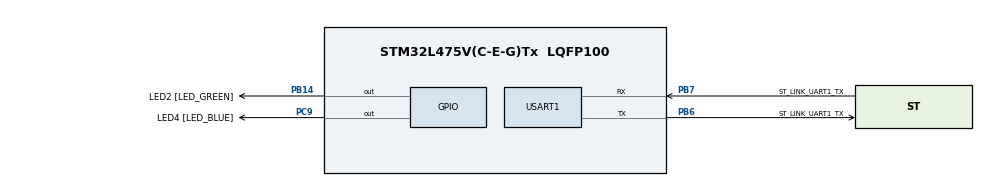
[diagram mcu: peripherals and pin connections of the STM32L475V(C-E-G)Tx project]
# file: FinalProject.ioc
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Mcu.Family=STM32L4
Mcu.Name=STM32L475V(C-E-G)Tx
Mcu.Package=LQFP100
NVIC.PriorityGroup=NVIC_PRIORITYGROUP_4
NVIC.RTC_Alarm_IRQn=true\:0\:0\:false\:false\:true\:true\:true\:true
NVIC.TIM2_IRQn=true\:0\:0\:false\:false\:true\:true\:true\:true
NVIC.TIM3_IRQn=true\:0\:0\:false\:false\:true\:true\:true\:true
NVIC.USART1_IRQn=true\:0\:0\:false\:false\:true\:true\:true\:true
PB14.GPIO_Label=LED2 [LED_GREEN]
PB14.Signal=GPIO_Output
PB6.GPIO_Label=ST_LINK_UART1_TX
PB6.Mode=Asynchronous
PB6.Signal=USART1_TX
PB7.GPIO_Label=ST_LINK_UART1_TX
PB7.Mode=Asynchronous
PB7.Signal=USART1_RX
PC9.GPIO_Label=LED4 [LED_BLUE]
PC9.Signal=GPIO_Output
ProjectManager.HeapSize=0x200
ProjectManager.StackSize=0x400
ProjectManager.TargetToolchain=STM32CubeIDE
RCC.HSE_VALUE=8000000
RCC.HSI_VALUE=16000000
RCC.LSE_VALUE=32768
RCC.MSI_VALUE=4000000
RCC.VCOOutputFreq_Value=32000000
RTC.Alarm-Alarm\ A=RTC_ALARM_A
USART1.VirtualMode-Asynchronous=VM_ASYNC
VP_IWDG_VS_IWDG.Mode=IWDG_Activate
VP_RTC_VS_RTC_Activate.Mode=RTC_Enabled
VP_RTC_VS_RTC_Alarm_A_Intern.Mode=Alarm A
VP_RTC_VS_RTC_Calendar.Mode=RTC_Calendar
VP_TIM2_VS_ClockSourceINT.Mode=Internal
VP_TIM3_VS_ClockSourceINT.Mode=Internal
board=custom

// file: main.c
/* USER CODE BEGIN Header */
/**
  ******************************************************************************
  * @file           : main.c
  * @brief          : Final Project
  * @author			: Fidel Quezada Guzman
  *
  ******************************************************************************
  * @attention
  *
  * Copyright (c) 2024 STMicroelectronics.
  * All rights reserved.
  *
  * This software is licensed under terms that can be found in the LICENSE file
  * in the root directory of this software component.
  * If no LICENSE file comes with this software, it is provided AS-IS.
  *
  ******************************************************************************
  */
/* USER CODE END Header */
#include "main.h"
/* USER CODE BEGIN Includes */
#include "string.h"
#include <stdio.h>						// Standard C Lib
#include "stm32l4xx.h"  				// STM32f4 series
/* USER CODE END Includes */
/* USER CODE BEGIN PTD */

// Boolean functionality
typedef enum
{
	FALSE, TRUE
} boolean;
/* USER CODE END PTD */
IWDG_HandleTypeDef hiwdg;
RTC_HandleTypeDef hrtc;
TIM_HandleTypeDef htim2;
TIM_HandleTypeDef htim3;
UART_HandleTypeDef huart1;
/* USER CODE BEGIN PV */

// UART input/output variables
char input[1] = { 0 };
volatile boolean TX_completed = FALSE;
char buffer[50];							// for printing w/ variables

// SW interrupt flag
volatile boolean SW_interrupt_detected = FALSE;

// Timer3 variables
volatile uint32_t timer3_count = 0;
const uint32_t MAX_COUNT = 10;
volatile boolean timer3_start = FALSE;

// RTC Alarm variables
volatile boolean rtc_alarm = FALSE;

/* USER CODE END PV */
void SystemClock_Config(void);
static void MX_GPIO_Init(void);
static void MX_IWDG_Init(void);
static void MX_RTC_Init(void);
static void MX_TIM2_Init(void);
static void MX_TIM3_Init(void);
static void MX_USART1_UART_Init(void);
/* USER CODE BEGIN PFP */

// Display the string on Terminal
void logMsg(UART_HandleTypeDef *huart, char _out[])
{
	// Run till completed
	HAL_UART_Transmit_IT(huart, (uint8_t *) _out, strlen(_out));
	do {
	} while (!TX_completed);
	TX_completed = FALSE;		// Reset once TX is completed
}

// Receive character from terminal
char logGetMsg(UART_HandleTypeDef *huart)
{
	HAL_UART_Receive_IT(huart, (uint8_t *) input, 1);
	return input[0];
}

// Board LEDs Toggle
void toggleGreenLED()
{
	HAL_GPIO_TogglePin(GPIOB, LED2_Pin);
	myDelay2(500);  							// Add custom delay made from SysTick
}
void toggleBlueLED()
{
	HAL_GPIO_TogglePin(GPIOC, LED4_Pin);
    myDelay1(500);								// Add custom delay made from Timer2
}

// Enable SW interrupt
void SWInterrupt(uint32_t IRQn)
{
	NVIC->STIR = IRQn;	// Trigger SW interrupt
}

// Custom Delay using Timer2
void myDelay1(uint32_t val)
{
    // Calculate required number of timer ticks based on desired delay
    uint32_t ticks = (HAL_RCC_GetHCLKFreq() / (htim2.Init.Prescaler + 1)) * val / 1000;

    // Configure Timer2 to start in interrupt mode
    HAL_TIM_Base_Start_IT(&htim2);

    // Reset Timer2 counter
    __HAL_TIM_SET_COUNTER(&htim2, 0);

    // Wait for required number of timer ticks. Get_Couter retrieves current value of Timer2
    while (__HAL_TIM_GET_COUNTER(&htim2) < ticks)
    {
        // Wait
    }
    // Stop Timer2
    HAL_TIM_Base_Stop_IT(&htim2);
}

// Custom Delay using SysTick to generate interrupts at specific freq, then wait for specific # of interrupts
void myDelay2(uint32_t val)
{
    // Configure SysTick to generate interrupts every 1ms
    SysTick_Config(SystemCoreClock / 1000);

    // Calculate required # of SysTick ticks based on the desired delay (in ms)
    uint32_t ticks = val;

    // Wait for # of SysTick ticks
    while (ticks > 0)
    {
        if (SysTick->CTRL & SysTick_CTRL_COUNTFLAG_Msk)
        {
            ticks--;
        }
    }

    // Disable SysTick
    SysTick->CTRL &= ~SysTick_CTRL_ENABLE_Msk;
}

/* USER CODE END PFP */
int main(void)
{
	/* MCU Configuration--------------------------------------------------------*/
	/* Reset of all peripherals, Initializes the Flash interface and the Systick. */
	HAL_Init();
	/* Configure the system clock */
	SystemClock_Config();
	/* Initialize all configured peripherals */
	MX_GPIO_Init();
	MX_IWDG_Init();
	MX_RTC_Init();
	MX_TIM2_Init();
	MX_TIM3_Init();
	MX_USART1_UART_Init();
	/* USER CODE BEGIN 2 */
	// Initial User Prompt
	logMsg(&huart1, "\n\n\n");
	logMsg(&huart1, "****************************************\n");
	logMsg(&huart1, "*           UCSD Winter 2024           *\n");
	logMsg(&huart1, "*    Embedded Real-Time Programming    *\n");
	logMsg(&huart1, "*        Fidel Quezada Guzman          *\n");
	logMsg(&huart1, "*           Final Project              *\n");
	logMsg(&huart1, "****************************************\n");
	logMsg(&huart1, "\n\n");
	logMsg(&huart1, "    Welcome to Embedded Controller Programming    \r\n");
	logMsg(&huart1, "**************************************************\n");
	logMsg(&huart1, "* Enter g for toggling Green LED                 *\r\n");
	logMsg(&huart1, "* Enter b for toggling Blue LED                  *\r\n");
	logMsg(&huart1, "* Enter s to generate SW interrupt               *\r\n");
	logMsg(&huart1, "* Enter t to start Timer 3                  	 *\r\n");
	logMsg(&huart1, "* Enter w to trigger Watchdog Reset              *\r\n");
	logMsg(&huart1, "**************************************************\n");
  /* USER CODE END 2 */
  /* Infinite loop */
  /* USER CODE BEGIN WHILE */
	while (1)
	{
	    // Pet Watchdog to prevent reset
	    HAL_IWDG_Refresh(&hiwdg);

		// Timer3 Print when hit 10s
		if (timer3_start)
		{
			timer3_count++;
			sprintf(buffer, "Timer3: %d seconds\r\n", timer3_count);
			logMsg(&huart1, buffer);
			if (timer3_count >= MAX_COUNT)
			{
				HAL_TIM_Base_Stop_IT(&htim3);
				sprintf(buffer, "Timer3 Final Count = %d\r\n", timer3_count);
				logMsg(&huart1, buffer);
				timer3_count = 0;
			}
			// reset
			timer3_start = FALSE;
		}

		// SW interrupt detected
		if (SW_interrupt_detected)
		{
			logMsg(&huart1, "SW Interrupt Detected! \r\n");
			SW_interrupt_detected = FALSE;		// Reset
		}

		// Display RTC Alarm
		if (rtc_alarm)
		{
			logMsg(&huart1, "1min RTC Alarm A Detected! \r\n");
			rtc_alarm = FALSE;					// Reset
		}

		// Let user input new char & Check if the received character is not null
		if (logGetMsg(&huart1) != '\0')
		{
			// Switch-case for character input
			switch (input[0])
			{
				case 'g':
					// Print Received Char & Toggle Green LED
					logMsg(&huart1, "Received char: g (Toggling Green LED)\n");
					toggleGreenLED();
					input[0] = '\0';
					break;
				case 'b':
					// Print Received Char & Toggle Blue LED
					logMsg(&huart1, "Received char: b (Toggling Blue LED)\n");
					toggleBlueLED();
					input[0] = '\0';
					break;
				case 's':
					// Print Received Char &
					logMsg(&huart1, "Received char: s (Generating SW Interrupt)\n");
					SWInterrupt(FMC_IRQn);
					input[0] = '\0';
					break;
				case 't':
					// Print Received Char & Start Timer3
	                logMsg(&huart1, "Received char: t (Starting Timer 3)\n");
	                HAL_TIM_Base_Start_IT(&htim3);
	                input[0] = '\0';
	                break;
				case 'w':
					// Print Received Char &
					logMsg(&huart1, "Received char: w (Triggering Watchdog Reset)\nSimulating Watchdog Reset w/ 1s Delay\n");
					myDelay2(1000);		// 1s Delay to have Watchdog be triggered
					input[0] = '\0';
					break;
				default:
					// Print Message to user.
					logMsg(&huart1, "Unknown character received\n");
					input[0] = '\0';
					break;
			}	// end of switch-case
		}	// end of if statement
		// Reset input string
    /* USER CODE END WHILE */
	}
}

void SystemClock_Config(void) {
	RCC_OscInitTypeDef RCC_OscInitStruct = { 0 };
	RCC_ClkInitTypeDef RCC_ClkInitStruct = { 0 };
	RCC_PeriphCLKInitTypeDef PeriphClkInit = { 0 };

	/** Configure LSE Drive Capability
	 */
	HAL_PWR_EnableBkUpAccess();
	__HAL_RCC_LSEDRIVE_CONFIG(RCC_LSEDRIVE_LOW);
	/** Initializes the CPU, AHB and APB busses clocks
	 */
	RCC_OscInitStruct.OscillatorType = RCC_OSCILLATORTYPE_LSI
			| RCC_OSCILLATORTYPE_LSE | RCC_OSCILLATORTYPE_MSI;
	RCC_OscInitStruct.LSEState = RCC_LSE_ON;
	RCC_OscInitStruct.LSIState = RCC_LSI_ON;
	RCC_OscInitStruct.MSIState = RCC_MSI_ON;
	RCC_OscInitStruct.MSICalibrationValue = 0;
	RCC_OscInitStruct.MSIClockRange = RCC_MSIRANGE_6;
	RCC_OscInitStruct.PLL.PLLState = RCC_PLL_ON;
	RCC_OscInitStruct.PLL.PLLSource = RCC_PLLSOURCE_MSI;
	RCC_OscInitStruct.PLL.PLLM = 1;
	RCC_OscInitStruct.PLL.PLLN = 40;
	RCC_OscInitStruct.PLL.PLLP = RCC_PLLP_DIV7;
	RCC_OscInitStruct.PLL.PLLQ = RCC_PLLQ_DIV2;
	RCC_OscInitStruct.PLL.PLLR = RCC_PLLR_DIV2;
	if (HAL_RCC_OscConfig(&RCC_OscInitStruct) != HAL_OK) {
		Error_Handler();
	}
	/** Initializes the CPU, AHB and APB busses clocks
	 */
	RCC_ClkInitStruct.ClockType = RCC_CLOCKTYPE_HCLK | RCC_CLOCKTYPE_SYSCLK
			| RCC_CLOCKTYPE_PCLK1 | RCC_CLOCKTYPE_PCLK2;
	RCC_ClkInitStruct.SYSCLKSource = RCC_SYSCLKSOURCE_PLLCLK;
	RCC_ClkInitStruct.AHBCLKDivider = RCC_SYSCLK_DIV1;
	RCC_ClkInitStruct.APB1CLKDivider = RCC_HCLK_DIV1;
	RCC_ClkInitStruct.APB2CLKDivider = RCC_HCLK_DIV1;

	if (HAL_RCC_ClockConfig(&RCC_ClkInitStruct, FLASH_LATENCY_4) != HAL_OK) {
		Error_Handler();
	}
	PeriphClkInit.PeriphClockSelection = RCC_PERIPHCLK_RTC
			| RCC_PERIPHCLK_USART1 | RCC_PERIPHCLK_USART3 | RCC_PERIPHCLK_I2C2
			| RCC_PERIPHCLK_DFSDM1 | RCC_PERIPHCLK_USB;
	PeriphClkInit.Usart1ClockSelection = RCC_USART1CLKSOURCE_PCLK2;
	PeriphClkInit.Usart3ClockSelection = RCC_USART3CLKSOURCE_PCLK1;
	PeriphClkInit.I2c2ClockSelection = RCC_I2C2CLKSOURCE_PCLK1;
	PeriphClkInit.Dfsdm1ClockSelection = RCC_DFSDM1CLKSOURCE_PCLK;
	PeriphClkInit.RTCClockSelection = RCC_RTCCLKSOURCE_LSI;
	PeriphClkInit.UsbClockSelection = RCC_USBCLKSOURCE_PLLSAI1;
	PeriphClkInit.PLLSAI1.PLLSAI1Source = RCC_PLLSOURCE_MSI;
	PeriphClkInit.PLLSAI1.PLLSAI1M = 1;
	PeriphClkInit.PLLSAI1.PLLSAI1N = 24;
	PeriphClkInit.PLLSAI1.PLLSAI1P = RCC_PLLP_DIV7;
	PeriphClkInit.PLLSAI1.PLLSAI1Q = RCC_PLLQ_DIV2;
	PeriphClkInit.PLLSAI1.PLLSAI1R = RCC_PLLR_DIV2;
	PeriphClkInit.PLLSAI1.PLLSAI1ClockOut = RCC_PLLSAI1_48M2CLK;
	if (HAL_RCCEx_PeriphCLKConfig(&PeriphClkInit) != HAL_OK) {
		Error_Handler();
	}
	/** Configure the main internal regulator output voltage
	 */
	if (HAL_PWREx_ControlVoltageScaling(PWR_REGULATOR_VOLTAGE_SCALE1)
			!= HAL_OK) {
		Error_Handler();
	}
	/** Enable MSI Auto calibration
	 */
	HAL_RCCEx_EnableMSIPLLMode();
}

static void MX_IWDG_Init(void)
{

	/*
	 * According to pre-set config, IWDG freq = 32kHz, so we need to adjust the default values
	 */

  hiwdg.Instance = IWDG;
  //hiwdg.Init.Prescaler = IWDG_PRESCALER_4;
  hiwdg.Init.Prescaler = IWDG_PRESCALER_256;  	// Adjust for 32 kHz

  //hiwdg.Init.Window = 4095;
  //hiwdg.Init.Reload = 4095;
  hiwdg.Init.Reload = 125;  					// Reload for timeout of .5s @ 32 kHz
  hiwdg.Init.Window = hiwdg.Init.Reload - 1;

  if (HAL_IWDG_Init(&hiwdg) != HAL_OK)
  {
    Error_Handler();
  }

}

static void MX_RTC_Init(void)
{

  RTC_TimeTypeDef sTime = {0};
  RTC_DateTypeDef sDate = {0};
  RTC_AlarmTypeDef sAlarm = {0};

  /** Initialize RTC Only
   */
  hrtc.Instance = RTC;
  hrtc.Init.HourFormat = RTC_HOURFORMAT_24;
  hrtc.Init.AsynchPrediv = 127;
  hrtc.Init.SynchPrediv = 255;
  hrtc.Init.OutPut = RTC_OUTPUT_DISABLE;
  hrtc.Init.OutPutRemap = RTC_OUTPUT_REMAP_NONE;
  hrtc.Init.OutPutPolarity = RTC_OUTPUT_POLARITY_HIGH;
  hrtc.Init.OutPutType = RTC_OUTPUT_TYPE_OPENDRAIN;
  if (HAL_RTC_Init(&hrtc) != HAL_OK)
  {
    Error_Handler();
  }

  /** Initialize RTC and set the Time and Date
  */
  sTime.Hours = 0x0;
  sTime.Minutes = 0x0;
  sTime.Seconds = 0x0;
  sTime.DayLightSaving = RTC_DAYLIGHTSAVING_NONE;
  sTime.StoreOperation = RTC_STOREOPERATION_RESET;
  if (HAL_RTC_SetTime(&hrtc, &sTime, RTC_FORMAT_BCD) != HAL_OK)
  {
    Error_Handler();
  }
  sDate.WeekDay = RTC_WEEKDAY_MONDAY;
  sDate.Month = RTC_MONTH_JANUARY;
  sDate.Date = 0x1;
  sDate.Year = 0x0;

  if (HAL_RTC_SetDate(&hrtc, &sDate, RTC_FORMAT_BCD) != HAL_OK)
  {
    Error_Handler();
  }

  /** Enable the Alarm A
  */
  sAlarm.AlarmTime.Hours = 0x0;
  sAlarm.AlarmTime.Minutes = 0x1;									// Trigger Alarm A in 1m
  sAlarm.AlarmTime.Seconds = 0x0;
  sAlarm.AlarmTime.SubSeconds = 0x0;
  sAlarm.AlarmTime.DayLightSaving = RTC_DAYLIGHTSAVING_NONE;
  sAlarm.AlarmTime.StoreOperation = RTC_STOREOPERATION_RESET;
  sAlarm.AlarmMask = RTC_ALARMMASK_NONE;
  sAlarm.AlarmSubSecondMask = RTC_ALARMSUBSECONDMASK_ALL;
  sAlarm.AlarmDateWeekDaySel = RTC_ALARMDATEWEEKDAYSEL_DATE;
  sAlarm.AlarmDateWeekDay = 0x1;
  sAlarm.Alarm = RTC_ALARM_A;
  if (HAL_RTC_SetAlarm_IT(&hrtc, &sAlarm, RTC_FORMAT_BCD) != HAL_OK)
  {
    Error_Handler();
  }

}

static void MX_TIM2_Init(void)
{

  TIM_ClockConfigTypeDef sClockSourceConfig = {0};
  TIM_MasterConfigTypeDef sMasterConfig = {0};

  htim2.Instance = TIM2;
  htim2.Init.Prescaler = HAL_RCC_GetHCLKFreq() / 1000 - 1;  // Set prescaler for a 1 ms resolution
  htim2.Init.CounterMode = TIM_COUNTERMODE_UP;
  htim2.Init.Period = 0xFFFF;  // Set a maximum period value
  htim2.Init.ClockDivision = TIM_CLOCKDIVISION_DIV1;
  htim2.Init.AutoReloadPreload = TIM_AUTORELOAD_PRELOAD_DISABLE;
  if (HAL_TIM_Base_Init(&htim2) != HAL_OK)
  {
    Error_Handler();
  }
  sClockSourceConfig.ClockSource = TIM_CLOCKSOURCE_INTERNAL;
  if (HAL_TIM_ConfigClockSource(&htim2, &sClockSourceConfig) != HAL_OK)
  {
    Error_Handler();
  }
  sMasterConfig.MasterOutputTrigger = TIM_TRGO_RESET;
  sMasterConfig.MasterSlaveMode = TIM_MASTERSLAVEMODE_DISABLE;
  if (HAL_TIMEx_MasterConfigSynchronization(&htim2, &sMasterConfig) != HAL_OK)
  {
    Error_Handler();
  }

}

static void MX_TIM3_Init(void)
{

  TIM_ClockConfigTypeDef sClockSourceConfig = {0};
  TIM_MasterConfigTypeDef sMasterConfig = {0};

  htim3.Instance = TIM3;
  htim3.Init.Prescaler = 8000 - 1; 									// Clock Freq = 80MHz. setting out prescalar to 8k will result in 10kHz Period
  htim3.Init.CounterMode = TIM_COUNTERMODE_UP;
  htim3.Init.Period = 10000 - 1;
  htim3.Init.ClockDivision = TIM_CLOCKDIVISION_DIV1;
  htim3.Init.AutoReloadPreload = TIM_AUTORELOAD_PRELOAD_ENABLE;

  if (HAL_TIM_Base_Init(&htim3) != HAL_OK)
  {
    Error_Handler();
  }
  sClockSourceConfig.ClockSource = TIM_CLOCKSOURCE_INTERNAL;
  if (HAL_TIM_ConfigClockSource(&htim3, &sClockSourceConfig) != HAL_OK)
  {
    Error_Handler();
  }
  sMasterConfig.MasterOutputTrigger = TIM_TRGO_RESET;
  sMasterConfig.MasterSlaveMode = TIM_MASTERSLAVEMODE_DISABLE;
  if (HAL_TIMEx_MasterConfigSynchronization(&htim3, &sMasterConfig) != HAL_OK)
  {
    Error_Handler();
  }

}

static void MX_USART1_UART_Init(void)
{

  huart1.Instance = USART1;
  huart1.Init.BaudRate = 115200;
  huart1.Init.WordLength = UART_WORDLENGTH_8B;
  huart1.Init.StopBits = UART_STOPBITS_1;
  huart1.Init.Parity = UART_PARITY_NONE;
  huart1.Init.Mode = UART_MODE_TX_RX;
  huart1.Init.HwFlowCtl = UART_HWCONTROL_NONE;
  huart1.Init.OverSampling = UART_OVERSAMPLING_16;
  huart1.Init.OneBitSampling = UART_ONE_BIT_SAMPLE_DISABLE;
  huart1.AdvancedInit.AdvFeatureInit = UART_ADVFEATURE_NO_INIT;
  if (HAL_UART_Init(&huart1) != HAL_OK)
  {
    Error_Handler();
  }

}

static void MX_GPIO_Init(void)
{
  GPIO_InitTypeDef GPIO_InitStruct = {0};

  /* GPIO Ports Clock Enable */
  __HAL_RCC_GPIOB_CLK_ENABLE();
  __HAL_RCC_GPIOC_CLK_ENABLE();

  /*Configure GPIO pin Output Level */
  HAL_GPIO_WritePin(LED2_GPIO_Port, LED2_Pin, GPIO_PIN_RESET);

  /*Configure GPIO pin Output Level */
  HAL_GPIO_WritePin(LED4_GPIO_Port, LED4_Pin, GPIO_PIN_RESET);

  /*Configure GPIO pin : LED2_Pin */
  GPIO_InitStruct.Pin = LED2_Pin;
  GPIO_InitStruct.Mode = GPIO_MODE_OUTPUT_PP;
  GPIO_InitStruct.Pull = GPIO_NOPULL;
  GPIO_InitStruct.Speed = GPIO_SPEED_FREQ_LOW;
  HAL_GPIO_Init(LED2_GPIO_Port, &GPIO_InitStruct);

  /*Configure GPIO pin : LED4_Pin */
  GPIO_InitStruct.Pin = LED4_Pin;
  GPIO_InitStruct.Mode = GPIO_MODE_OUTPUT_PP;
  GPIO_InitStruct.Pull = GPIO_NOPULL;
  GPIO_InitStruct.Speed = GPIO_SPEED_FREQ_LOW;
  HAL_GPIO_Init(LED4_GPIO_Port, &GPIO_InitStruct);

  // Enable and set FMC_IRQn Interrupt to the lowest priority
  HAL_NVIC_SetPriority(FMC_IRQn, 0, 0);
  HAL_NVIC_EnableIRQ(FMC_IRQn);

}

/* USER CODE BEGIN 4 */

// UART Transmission
void HAL_UART_TxCpltCallback(UART_HandleTypeDef *huart)
{
	if (huart->Instance == USART1)
		TX_completed = TRUE;
}

// Function that will be called upon when Timer3 expires
void HAL_TIM_PeriodElapsedCallback(TIM_HandleTypeDef *htim)
{
	if (htim->Instance == htim3.Instance)
	{
		timer3_start = TRUE;
	}
}

// RTC Alarm A callback
void HAL_RTC_AlarmAEventCallback(RTC_HandleTypeDef *hrtc)
{
	rtc_alarm = TRUE;
}
/* USER CODE END 4 */
void Error_Handler(void)
{
  __disable_irq();
  while (1)
  {
  }
}
